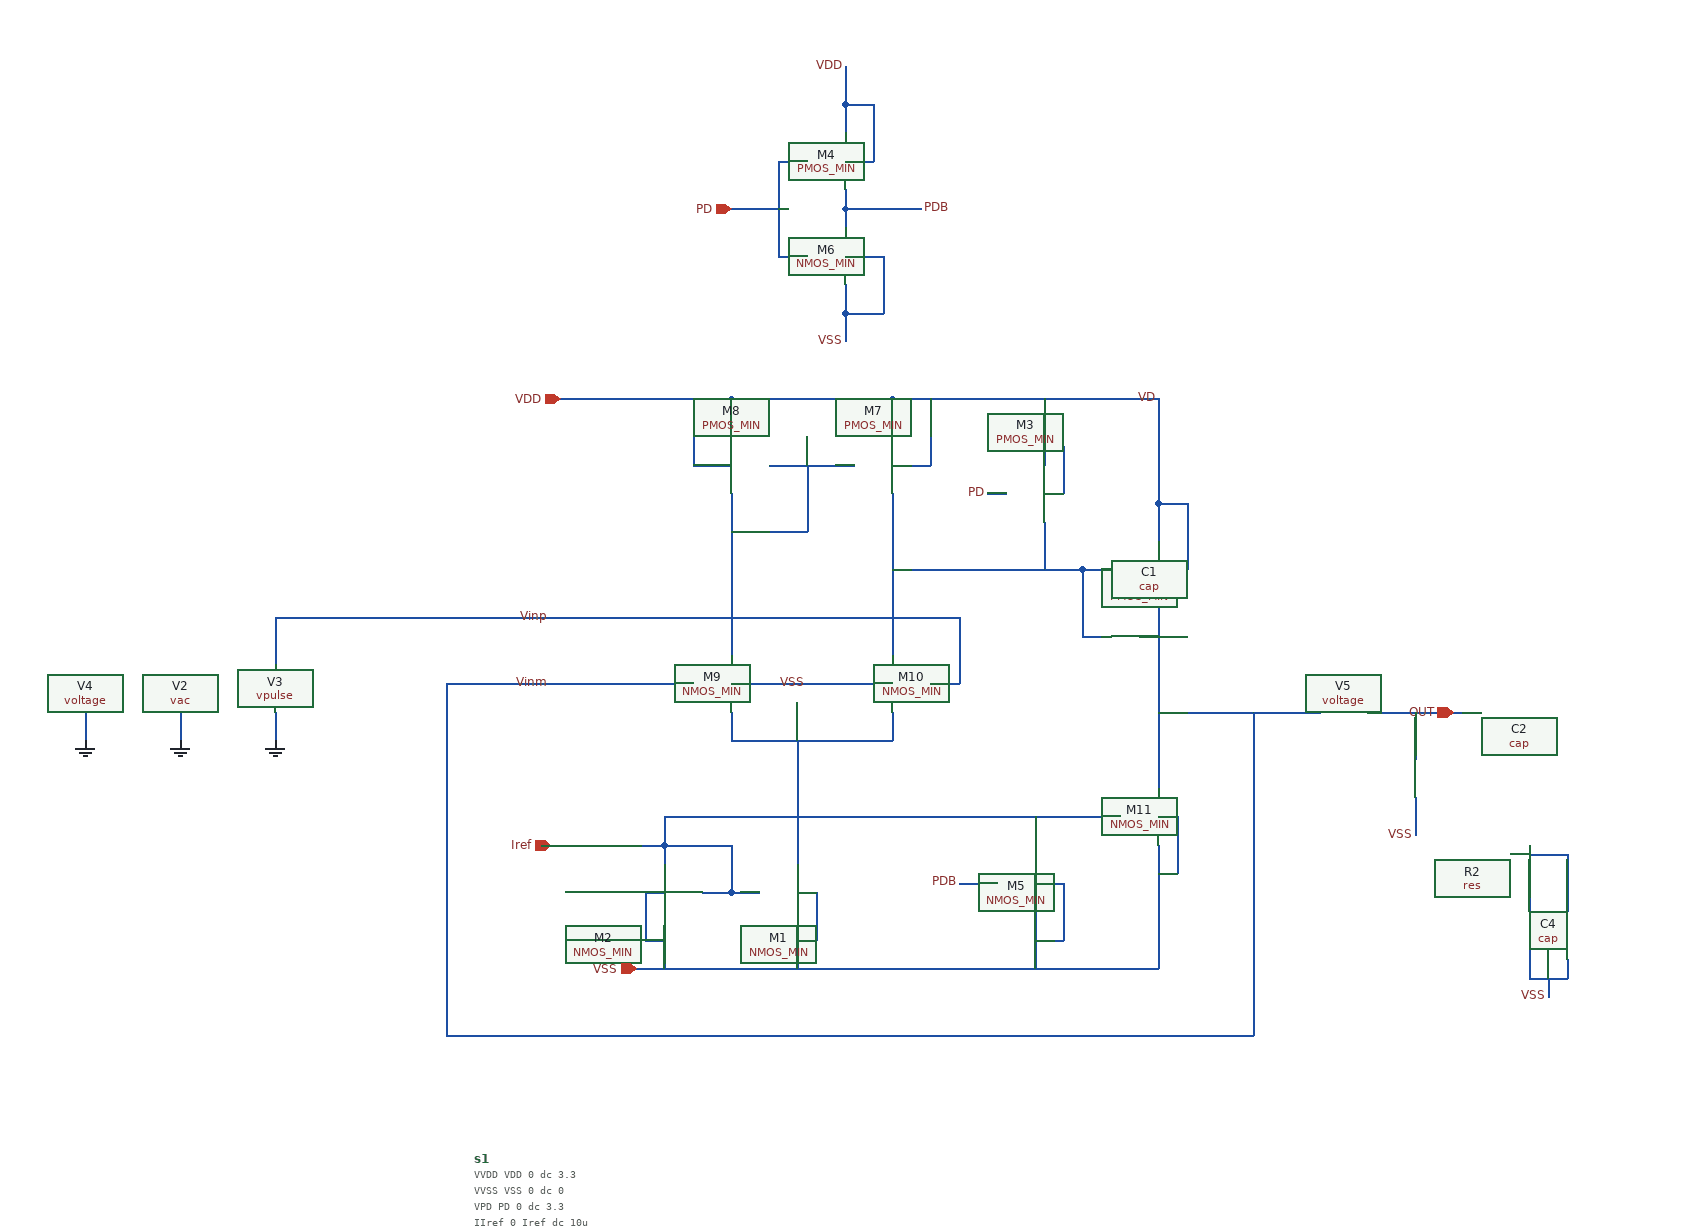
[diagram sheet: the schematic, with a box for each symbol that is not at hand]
v {xschem version=3.4.8RC file_version=1.3}
G {}
K {}
V {}
S {}
F {}
E {}
N 330 -340 360 -340 {lab=VDD}
N -300 -520 -120 -520 {lab=VDD}
N -120 -520 -120 -480 {lab=VDD}
N -120 -520 50 -520 {lab=VDD}
N 50 -520 50 -480 {lab=VDD}
N 50 -520 230 -520 {lab=VDD}
N 330 -520 330 -410 {lab=VDD}
N 360 -410 360 -340 {lab=VDD}
N 330 -410 360 -410 {lab=VDD}
N 50 -450 90 -450 {lab=VDD}
N 90 -520 90 -450 {lab=VDD}
N -160 -450 -120 -450 {lab=VDD}
N -160 -520 -160 -450 {lab=VDD}
N -40 -450 -40 -400 {lab=#net1}
N -120 -380 -40 -380 {lab=#net1}
N -300 -290 120 -290 {lab=Vinp}
N 120 -290 120 -220 {lab=Vinp}
N 90 -220 120 -220 {lab=Vinp}
N -120 -190 -120 -160 {lab=#net2}
N -120 -160 50 -160 {lab=#net2}
N 50 -190 50 -160 {lab=#net2}
N -120 -220 50 -220 {lab=VSS}
N -80 -450 10 -450 {lab=#net1}
N 0 80 230 80 {lab=VSS}
N -240 -220 -160 -220 {lab=Vinm}
N -260 -220 -240 -220 {lab=Vinm}
N -50 30 -50 80 {lab=VSS}
N -50 0 -30 0 {lab=VSS}
N -30 0 -30 50 {lab=VSS}
N -50 50 -30 50 {lab=VSS}
N -220 80 0 80 {lab=VSS}
N -120 0 -90 0 {lab=Iref}
N -150 0 -120 0 {lab=Iref}
N -190 30 -190 80 {lab=VSS}
N -210 0 -190 0 {lab=VSS}
N -210 0 -210 50 {lab=VSS}
N -210 50 -190 50 {lab=VSS}
N 50 -340 110 -340 {lab=#net3}
N -120 -50 -120 0 {lab=Iref}
N -190 -50 -120 -50 {lab=Iref}
N -320 -50 -190 -50 {lab=Iref}
N -190 -50 -190 -30 {lab=Iref}
N -190 -80 -190 -50 {lab=Iref}
N 330 -310 330 -280 {lab=Vinm}
N 290 -520 330 -520 {lab=VDD}
N 250 -340 290 -340 {lab=#net3}
N 250 -340 250 -270 {lab=#net3}
N 330 -50 330 80 {lab=VSS}
N 290 80 330 80 {lab=VSS}
N 330 -80 350 -80 {lab=VSS}
N 350 -80 350 -20 {lab=VSS}
N 330 -20 350 -20 {lab=VSS}
N -420 150 340 150 {lab=Vinm}
N -420 -220 -420 150 {lab=Vinm}
N -420 -220 -260 -220 {lab=Vinm}
N -50 -120 -50 -30 {lab=#net2}
N 430 -190 430 140 {lab=Vinm}
N 310 -270 330 -270 {lab=Vinm}
N 250 -270 270 -270 {lab=#net3}
N -50 -160 -50 -140 {lab=#net2}
N 330 -280 330 -180 {lab=Vinm}
N 110 -340 140 -340 {lab=#net3}
N 330 -180 330 -160 {lab=Vinm}
N 140 -340 190 -340 {lab=#net3}
N -120 -420 -120 -250 {lab=#net1}
N -40 -400 -40 -380 {lab=#net1}
N 50 -420 50 -250 {lab=#net3}
N 330 -410 330 -380 {lab=VDD}
N 330 -380 330 -370 {lab=VDD}
N -50 -140 -50 -120 {lab=#net2}
N -600 -290 -300 -290 {lab=Vinp}
N 200 20 200 60 {lab=VSS}
N 120 -10 160 -10 {lab=PDB}
N 200 -80 200 -50 {lab=Iref}
N 200 -10 230 -10 {lab=VSS}
N 230 -10 230 50 {lab=VSS}
N 200 50 230 50 {lab=VSS}
N 200 -50 200 -40 {lab=Iref}
N 200 60 200 80 {lab=VSS}
N 210 -470 210 -450 {lab=VDD}
N 210 -420 230 -420 {lab=VDD}
N 230 -470 230 -420 {lab=VDD}
N 210 -470 230 -470 {lab=VDD}
N 210 -380 210 -340 {lab=#net3}
N 150 -420 170 -420 {lab=PD}
N 330 -190 500 -190 {lab=Vinm}
N 330 -160 330 -110 {lab=Vinm}
N -190 -80 140 -80 {lab=Iref}
N 190 -340 250 -340 {lab=#net3}
N 230 -520 290 -520 {lab=VDD}
N 210 -390 210 -380 {lab=#net3}
N 210 -520 210 -470 {lab=VDD}
N 230 80 290 80 {lab=VSS}
N 140 -80 290 -80 {lab=Iref}
N 0 -830 0 -800 {lab=VDD}
N 0 -670 40 -670 {lab=VSS}
N 40 -670 40 -610 {lab=VSS}
N 0 -610 40 -610 {lab=VSS}
N 0 -770 30 -770 {lab=VDD}
N 30 -830 30 -770 {lab=VDD}
N 0 -830 30 -830 {lab=VDD}
N 0 -720 0 -700 {lab=PDB}
N 0 -640 0 -610 {lab=VSS}
N 0 -840 0 -830 {lab=VDD}
N 0 -740 0 -720 {lab=PDB}
N 0 -610 0 -580 {lab=VSS}
N -70 -770 -40 -770 {lab=PD}
N -70 -770 -70 -670 {lab=PD}
N -70 -670 -40 -670 {lab=PD}
N 0 -850 0 -840 {lab=VDD}
N 0 -870 0 -850 {lab=VDD}
N -120 -720 -70 -720 {lab=PD}
N 0 -720 80 -720 {lab=PDB}
N 340 150 430 150 {lab=Vinm}
N 430 140 430 150 {lab=Vinm}
N -600 -290 -600 -240 {lab=Vinp}
N -700 -190 -700 -160 {lab=GND}
N -600 -190 -600 -160 {lab=GND}
N -800 -190 -800 -160 {lab=GND}
N 720 60 720 90 {lab=VSS}
N 740 90 740 110 {lab=VSS}
N 720 -20 720 20 {lab=#net4}
N 720 -50 720 -20 {lab=#net4}
N 720 -40 760 -40 {lab=#net4}
N 760 -40 760 20 {lab=#net4}
N 760 70 760 90 {lab=VSS}
N 720 90 760 90 {lab=VSS}
N 600 -190 600 -140 {lab=OUT}
N 600 -100 600 -60 {lab=VSS}
N 550 -190 650 -190 {lab=OUT}
C {PMOS_MIN.sym} 10 -450 0 0 {name=M7 model=p3.0 w=20u l=1u as=0 ps=0 ad=0 pd=0 m=1}
C {PMOS_MIN.sym} -80 -450 0 1 {name=M8 model=p3.0 w=20u l=1u as=0 ps=0 ad=0 pd=0 m=1}
C {NMOS_MIN.sym} -160 -220 0 0 {name=M9 model=n3.0 w=10u l=1u as=0 ps=0 ad=0 pd=0 m=1}
C {NMOS_MIN.sym} 90 -220 0 1 {name=M10 model=n3.0 w=10u l=1u as=0 ps=0 ad=0 pd=0 m=1}
C {NMOS_MIN.sym} 290 -80 0 0 {name=M11 model=n3.0 w=10u l=1u as=0 ps=0 ad=0 pd=0 m=6}
C {PMOS_MIN.sym} 290 -340 0 0 {name=M12 model=p3.0 w=20u l=1u as=0 ps=0 ad=0 pd=0 m=6}
C {ipin.sym} -300 -520 0 0 {name=p5 lab=VDD}
C {iopin.sym} 640 -190 0 0 {name=p7 lab=OUT}
C {ipin.sym} -310 -50 0 0 {name=p1 lab=Iref}
C {NMOS_MIN.sym} -90 0 0 0 {name=M1 model=n3.0 w=10u l=1u as=0 ps=0 ad=0 pd=0 m=1}
C {NMOS_MIN.sym} -150 0 0 1 {name=M2 model=n3.0 w=10u l=1u as=0 ps=0 ad=0 pd=0 m=1}
C {lab_pin.sym} -310 -290 1 0 {name=l3 sig_type=std_logic lab=Vinp}
C {lab_pin.sym} -40 -220 1 0 {name=l5 sig_type=std_logic lab=VSS}
C {ipin.sym} -220 80 0 0 {name=p2 lab=VSS}
C {cap.sym} 310 -280 1 0 {name=C1
m=1
value=140f
footprint=1206
device=ceramic}
C {lab_pin.sym} -310 -220 3 0 {name=l8 sig_type=std_logic lab=Vinm}
C {NMOS_MIN.sym} 160 -10 0 0 {name=M5 model=n3.0 w=3.5u l=0.35u as=0 ps=0 ad=0 pd=0 m=1}
C {PMOS_MIN.sym} 170 -420 0 0 {name=M3 model=p3.0 w=3.5u l=0.35u as=0 ps=0 ad=0 pd=0 m=1}
C {PMOS_MIN.sym} -40 -770 0 0 {name=M4 model=p3.0 w=3.5u l=0.35u as=0 ps=0 ad=0 pd=0 m=1}
C {NMOS_MIN.sym} -40 -670 0 0 {name=M6 model=n3.0 w=3.5u l=0.35u as=0 ps=0 ad=0 pd=0 m=1}
C {lab_pin.sym} 0 -870 1 0 {name=l1 sig_type=std_logic lab=VDD}
C {lab_pin.sym} 0 -580 3 0 {name=l4 sig_type=std_logic lab=VSS}
C {ipin.sym} -120 -720 0 0 {name=p4 lab=PD}
C {lab_pin.sym} 80 -720 2 0 {name=l6 sig_type=std_logic lab=PDB}
C {lab_pin.sym} 120 -10 0 0 {name=l7 sig_type=std_logic lab=PDB}
C {lab_pin.sym} 150 -420 0 0 {name=l9 sig_type=std_logic lab=PD}
C {gnd.sym} -700 -160 0 0 {name=l15 lab=GND}
C {vac.sym} -700 -250 0 0 {name=V2 value="1.65 ac 1"}
C {vpulse.sym} -600 -250 0 0 {name=V3 value="pulse(0 3.3 100n 1n 1n 200n 400n)"}
C {gnd.sym} -600 -160 0 0 {name=l10 lab=GND}
C {voltage.sym} -800 -250 0 0 {name=V4 value=3.3}
C {gnd.sym} -800 -160 0 0 {name=l11 lab=GND}
C {res.sym} 750 10 0 0 {name=R2
value=1meg
footprint=1206
device=resistor
m=1}
C {lab_pin.sym} 740 110 3 0 {name=l14 sig_type=std_logic lab=VSS}
C {cap.sym} 730 60 2 0 {name=C4
m=1
value=1p
footprint=1206
device=ceramic}
C {code_shown.sym} -390 280 0 0 {name=s1 only_toplevel=false value=
"
VVDD VDD 0 dc 3.3
VVSS VSS 0 dc 0
VPD PD 0 dc 3.3
IIref 0 Iref dc 10u

*VVIN+ VIN+ 0 pulse(0 3.3 100n 1n 1n 200n 400n)
*VVIN+ VIN+ 0 dc 0

.probe <alli>
.meas TRAN IOUTMAX MAX I(V5)
.meas TRAN IOUTMIN MIN I(V5)
*.meas TRAN VusH TRIG V(OUT) VAL=0.33 RISE=1 TARG V(OUT) VAL=2.97 RISE=1
*.meas TRAN VusL TRIG V(OUT) VAL=2.97 FALL=1 TARG V(OUT) VAL=0.33 FALL=1
*.meas TRAN OUTMAX MAX V(OUT) from=0 to=3u

.include /home/raidonn/LRCircuit/spicemodel/ocs65_stl_n3_typ.para
.include /home/raidonn/LRCircuit/spicemodel/ocs65_stl_p3_typ.para

.control
save all
*dc V3 0 3.3 0.01
*dc V1 0 3.3 0.01
*ac dec 10 1k 1g
tran 1n 500n
*plot V(Vinp) V(OUT)
plot I(V5)
*plot db(OUT/(OUT-Vinp)) ph(OUT/(OUT-Vinp))*180/3.14

write "Opamp_ACsim_ver3.raw"

.endc"
}
C {lab_pin.sym} 600 -60 3 0 {name=l2 sig_type=std_logic lab=VSS}
C {voltage.sym} 490 -190 3 0 {name=V5 value=0}
C {cap.sym} 610 -100 2 0 {name=C2
m=1
value=1p
footprint=1206
device=ceramic}
C {lab_pin.sym} 330 -520 1 0 {name=l13 sig_type=std_logic lab=VD}
